VERSION 5.8 ;
BUSBITCHARS "[]" ;
DIVIDERCHAR "/" ;
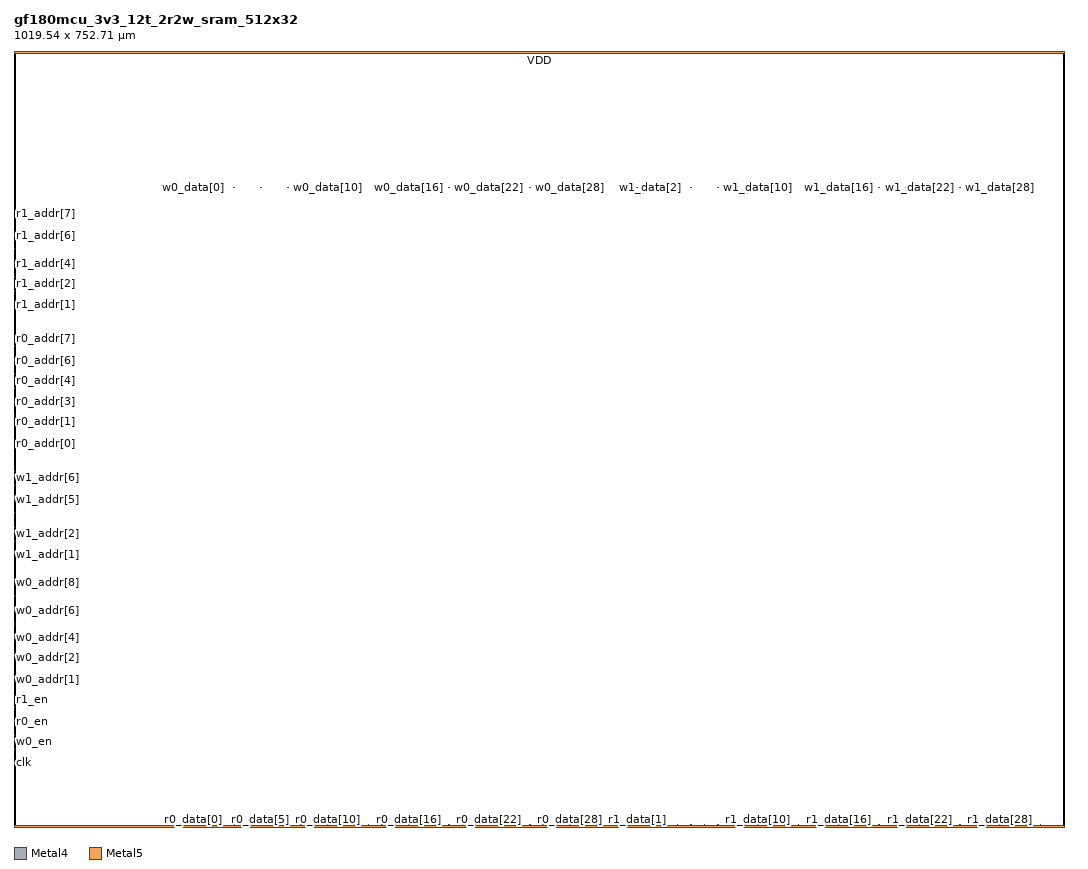
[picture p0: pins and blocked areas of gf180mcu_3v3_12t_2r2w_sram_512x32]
MACRO gf180mcu_3v3_12t_2r2w_sram_512x32
  CLASS BLOCK ;
  FOREIGN gf180mcu_3v3_12t_2r2w_sram_512x32 0.000 0.000 ;
  ORIGIN 0.000 0.000 ;
  SIZE 1019.545000 BY 752.710000 ;
  SYMMETRY X Y ;
  PIN clk
    DIRECTION INPUT ;
    USE SIGNAL ;
    PORT
      LAYER Metal4 ;
        RECT 0.320000 61.970000 0.960000 62.610000 ;
    END
  END clk
  PIN w0_en
    DIRECTION INPUT ;
    USE SIGNAL ;
    PORT
      LAYER Metal4 ;
        RECT 0.320000 75.455000 0.960000 76.095000 ;
    END
  END w0_en
  PIN w1_en
    DIRECTION INPUT ;
    USE SIGNAL ;
    PORT
      LAYER Metal4 ;
        RECT 0.320000 88.935000 0.960000 89.575000 ;
    END
  END w1_en
  PIN r0_en
    DIRECTION INPUT ;
    USE SIGNAL ;
    PORT
      LAYER Metal4 ;
        RECT 0.320000 102.415000 0.960000 103.055000 ;
    END
  END r0_en
  PIN r1_en
    DIRECTION INPUT ;
    USE SIGNAL ;
    PORT
      LAYER Metal4 ;
        RECT 0.320000 115.900000 0.960000 116.540000 ;
    END
  END r1_en
  PIN w0_addr[0]
    DIRECTION INPUT ;
    USE SIGNAL ;
    PORT
      LAYER Metal4 ;
        RECT 0.320000 129.380000 0.960000 130.020000 ;
    END
  END w0_addr[0]
  PIN w0_addr[1]
    DIRECTION INPUT ;
    USE SIGNAL ;
    PORT
      LAYER Metal4 ;
        RECT 0.320000 142.865000 0.960000 143.505000 ;
    END
  END w0_addr[1]
  PIN w0_addr[2]
    DIRECTION INPUT ;
    USE SIGNAL ;
    PORT
      LAYER Metal4 ;
        RECT 0.320000 156.345000 0.960000 156.985000 ;
    END
  END w0_addr[2]
  PIN w0_addr[3]
    DIRECTION INPUT ;
    USE SIGNAL ;
    PORT
      LAYER Metal4 ;
        RECT 0.320000 169.825000 0.960000 170.465000 ;
    END
  END w0_addr[3]
  PIN w0_addr[4]
    DIRECTION INPUT ;
    USE SIGNAL ;
    PORT
      LAYER Metal4 ;
        RECT 0.320000 183.310000 0.960000 183.950000 ;
    END
  END w0_addr[4]
  PIN w0_addr[5]
    DIRECTION INPUT ;
    USE SIGNAL ;
    PORT
      LAYER Metal4 ;
        RECT 0.320000 196.790000 0.960000 197.430000 ;
    END
  END w0_addr[5]
  PIN w0_addr[6]
    DIRECTION INPUT ;
    USE SIGNAL ;
    PORT
      LAYER Metal4 ;
        RECT 0.320000 210.270000 0.960000 210.910000 ;
    END
  END w0_addr[6]
  PIN w0_addr[7]
    DIRECTION INPUT ;
    USE SIGNAL ;
    PORT
      LAYER Metal4 ;
        RECT 0.320000 223.755000 0.960000 224.395000 ;
    END
  END w0_addr[7]
  PIN w0_addr[8]
    DIRECTION INPUT ;
    USE SIGNAL ;
    PORT
      LAYER Metal4 ;
        RECT 0.320000 237.235000 0.960000 237.875000 ;
    END
  END w0_addr[8]
  PIN w1_addr[0]
    DIRECTION INPUT ;
    USE SIGNAL ;
    PORT
      LAYER Metal4 ;
        RECT 0.320000 250.720000 0.960000 251.360000 ;
    END
  END w1_addr[0]
  PIN w1_addr[1]
    DIRECTION INPUT ;
    USE SIGNAL ;
    PORT
      LAYER Metal4 ;
        RECT 0.320000 264.200000 0.960000 264.840000 ;
    END
  END w1_addr[1]
  PIN w1_addr[2]
    DIRECTION INPUT ;
    USE SIGNAL ;
    PORT
      LAYER Metal4 ;
        RECT 0.320000 277.680000 0.960000 278.320000 ;
    END
  END w1_addr[2]
  PIN w1_addr[3]
    DIRECTION INPUT ;
    USE SIGNAL ;
    PORT
      LAYER Metal4 ;
        RECT 0.320000 291.165000 0.960000 291.805000 ;
    END
  END w1_addr[3]
  PIN w1_addr[4]
    DIRECTION INPUT ;
    USE SIGNAL ;
    PORT
      LAYER Metal4 ;
        RECT 0.320000 304.645000 0.960000 305.285000 ;
    END
  END w1_addr[4]
  PIN w1_addr[5]
    DIRECTION INPUT ;
    USE SIGNAL ;
    PORT
      LAYER Metal4 ;
        RECT 0.320000 318.130000 0.960000 318.770000 ;
    END
  END w1_addr[5]
  PIN w1_addr[6]
    DIRECTION INPUT ;
    USE SIGNAL ;
    PORT
      LAYER Metal4 ;
        RECT 0.320000 331.610000 0.960000 332.250000 ;
    END
  END w1_addr[6]
  PIN w1_addr[7]
    DIRECTION INPUT ;
    USE SIGNAL ;
    PORT
      LAYER Metal4 ;
        RECT 0.320000 345.090000 0.960000 345.730000 ;
    END
  END w1_addr[7]
  PIN w1_addr[8]
    DIRECTION INPUT ;
    USE SIGNAL ;
    PORT
      LAYER Metal4 ;
        RECT 0.320000 358.575000 0.960000 359.215000 ;
    END
  END w1_addr[8]
  PIN r0_addr[0]
    DIRECTION INPUT ;
    USE SIGNAL ;
    PORT
      LAYER Metal4 ;
        RECT 0.320000 372.055000 0.960000 372.695000 ;
    END
  END r0_addr[0]
  PIN r0_addr[1]
    DIRECTION INPUT ;
    USE SIGNAL ;
    PORT
      LAYER Metal4 ;
        RECT 0.320000 385.540000 0.960000 386.180000 ;
    END
  END r0_addr[1]
  PIN r0_addr[2]
    DIRECTION INPUT ;
    USE SIGNAL ;
    PORT
      LAYER Metal4 ;
        RECT 0.320000 399.020000 0.960000 399.660000 ;
    END
  END r0_addr[2]
  PIN r0_addr[3]
    DIRECTION INPUT ;
    USE SIGNAL ;
    PORT
      LAYER Metal4 ;
        RECT 0.320000 412.500000 0.960000 413.140000 ;
    END
  END r0_addr[3]
  PIN r0_addr[4]
    DIRECTION INPUT ;
    USE SIGNAL ;
    PORT
      LAYER Metal4 ;
        RECT 0.320000 425.985000 0.960000 426.625000 ;
    END
  END r0_addr[4]
  PIN r0_addr[5]
    DIRECTION INPUT ;
    USE SIGNAL ;
    PORT
      LAYER Metal4 ;
        RECT 0.320000 439.465000 0.960000 440.105000 ;
    END
  END r0_addr[5]
  PIN r0_addr[6]
    DIRECTION INPUT ;
    USE SIGNAL ;
    PORT
      LAYER Metal4 ;
        RECT 0.320000 452.950000 0.960000 453.590000 ;
    END
  END r0_addr[6]
  PIN r0_addr[7]
    DIRECTION INPUT ;
    USE SIGNAL ;
    PORT
      LAYER Metal4 ;
        RECT 0.320000 466.430000 0.960000 467.070000 ;
    END
  END r0_addr[7]
  PIN r0_addr[8]
    DIRECTION INPUT ;
    USE SIGNAL ;
    PORT
      LAYER Metal4 ;
        RECT 0.320000 479.910000 0.960000 480.550000 ;
    END
  END r0_addr[8]
  PIN r1_addr[0]
    DIRECTION INPUT ;
    USE SIGNAL ;
    PORT
      LAYER Metal4 ;
        RECT 0.320000 493.395000 0.960000 494.035000 ;
    END
  END r1_addr[0]
  PIN r1_addr[1]
    DIRECTION INPUT ;
    USE SIGNAL ;
    PORT
      LAYER Metal4 ;
        RECT 0.320000 506.875000 0.960000 507.515000 ;
    END
  END r1_addr[1]
  PIN r1_addr[2]
    DIRECTION INPUT ;
    USE SIGNAL ;
    PORT
      LAYER Metal4 ;
        RECT 0.320000 520.355000 0.960000 520.995000 ;
    END
  END r1_addr[2]
  PIN r1_addr[3]
    DIRECTION INPUT ;
    USE SIGNAL ;
    PORT
      LAYER Metal4 ;
        RECT 0.320000 533.840000 0.960000 534.480000 ;
    END
  END r1_addr[3]
  PIN r1_addr[4]
    DIRECTION INPUT ;
    USE SIGNAL ;
    PORT
      LAYER Metal4 ;
        RECT 0.320000 547.320000 0.960000 547.960000 ;
    END
  END r1_addr[4]
  PIN r1_addr[5]
    DIRECTION INPUT ;
    USE SIGNAL ;
    PORT
      LAYER Metal4 ;
        RECT 0.320000 560.805000 0.960000 561.445000 ;
    END
  END r1_addr[5]
  PIN r1_addr[6]
    DIRECTION INPUT ;
    USE SIGNAL ;
    PORT
      LAYER Metal4 ;
        RECT 0.320000 574.285000 0.960000 574.925000 ;
    END
  END r1_addr[6]
  PIN r1_addr[7]
    DIRECTION INPUT ;
    USE SIGNAL ;
    PORT
      LAYER Metal4 ;
        RECT 0.320000 587.765000 0.960000 588.405000 ;
    END
  END r1_addr[7]
  PIN r1_addr[8]
    DIRECTION INPUT ;
    USE SIGNAL ;
    PORT
      LAYER Metal4 ;
        RECT 0.320000 601.250000 0.960000 601.890000 ;
    END
  END r1_addr[8]
  PIN w0_data[0]
    DIRECTION INPUT ;
    USE SIGNAL ;
    PORT
      LAYER Metal5 ;
        RECT 174.205000 620.630000 174.845000 621.270000 ;
    END
  END w0_data[0]
  PIN w0_data[1]
    DIRECTION INPUT ;
    USE SIGNAL ;
    PORT
      LAYER Metal5 ;
        RECT 187.260000 620.630000 187.900000 621.270000 ;
    END
  END w0_data[1]
  PIN w0_data[2]
    DIRECTION INPUT ;
    USE SIGNAL ;
    PORT
      LAYER Metal5 ;
        RECT 200.310000 620.630000 200.950000 621.270000 ;
    END
  END w0_data[2]
  PIN w0_data[3]
    DIRECTION INPUT ;
    USE SIGNAL ;
    PORT
      LAYER Metal5 ;
        RECT 213.360000 620.630000 214.000000 621.270000 ;
    END
  END w0_data[3]
  PIN w0_data[4]
    DIRECTION INPUT ;
    USE SIGNAL ;
    PORT
      LAYER Metal5 ;
        RECT 226.415000 620.630000 227.055000 621.270000 ;
    END
  END w0_data[4]
  PIN w0_data[5]
    DIRECTION INPUT ;
    USE SIGNAL ;
    PORT
      LAYER Metal5 ;
        RECT 239.465000 620.630000 240.105000 621.270000 ;
    END
  END w0_data[5]
  PIN w0_data[6]
    DIRECTION INPUT ;
    USE SIGNAL ;
    PORT
      LAYER Metal5 ;
        RECT 252.515000 620.630000 253.155000 621.270000 ;
    END
  END w0_data[6]
  PIN w0_data[7]
    DIRECTION INPUT ;
    USE SIGNAL ;
    PORT
      LAYER Metal5 ;
        RECT 265.570000 620.630000 266.210000 621.270000 ;
    END
  END w0_data[7]
  PIN w0_data[8]
    DIRECTION INPUT ;
    USE SIGNAL ;
    PORT
      LAYER Metal5 ;
        RECT 278.620000 620.630000 279.260000 621.270000 ;
    END
  END w0_data[8]
  PIN w0_data[9]
    DIRECTION INPUT ;
    USE SIGNAL ;
    PORT
      LAYER Metal5 ;
        RECT 291.675000 620.630000 292.315000 621.270000 ;
    END
  END w0_data[9]
  PIN w0_data[10]
    DIRECTION INPUT ;
    USE SIGNAL ;
    PORT
      LAYER Metal5 ;
        RECT 304.725000 620.630000 305.365000 621.270000 ;
    END
  END w0_data[10]
  PIN w0_data[11]
    DIRECTION INPUT ;
    USE SIGNAL ;
    PORT
      LAYER Metal5 ;
        RECT 317.775000 620.630000 318.415000 621.270000 ;
    END
  END w0_data[11]
  PIN w0_data[12]
    DIRECTION INPUT ;
    USE SIGNAL ;
    PORT
      LAYER Metal5 ;
        RECT 330.830000 620.630000 331.470000 621.270000 ;
    END
  END w0_data[12]
  PIN w0_data[13]
    DIRECTION INPUT ;
    USE SIGNAL ;
    PORT
      LAYER Metal5 ;
        RECT 343.880000 620.630000 344.520000 621.270000 ;
    END
  END w0_data[13]
  PIN w0_data[14]
    DIRECTION INPUT ;
    USE SIGNAL ;
    PORT
      LAYER Metal5 ;
        RECT 356.930000 620.630000 357.570000 621.270000 ;
    END
  END w0_data[14]
  PIN w0_data[15]
    DIRECTION INPUT ;
    USE SIGNAL ;
    PORT
      LAYER Metal5 ;
        RECT 369.985000 620.630000 370.625000 621.270000 ;
    END
  END w0_data[15]
  PIN w0_data[16]
    DIRECTION INPUT ;
    USE SIGNAL ;
    PORT
      LAYER Metal5 ;
        RECT 383.035000 620.630000 383.675000 621.270000 ;
    END
  END w0_data[16]
  PIN w0_data[17]
    DIRECTION INPUT ;
    USE SIGNAL ;
    PORT
      LAYER Metal5 ;
        RECT 396.090000 620.630000 396.730000 621.270000 ;
    END
  END w0_data[17]
  PIN w0_data[18]
    DIRECTION INPUT ;
    USE SIGNAL ;
    PORT
      LAYER Metal5 ;
        RECT 409.140000 620.630000 409.780000 621.270000 ;
    END
  END w0_data[18]
  PIN w0_data[19]
    DIRECTION INPUT ;
    USE SIGNAL ;
    PORT
      LAYER Metal5 ;
        RECT 422.190000 620.630000 422.830000 621.270000 ;
    END
  END w0_data[19]
  PIN w0_data[20]
    DIRECTION INPUT ;
    USE SIGNAL ;
    PORT
      LAYER Metal5 ;
        RECT 435.245000 620.630000 435.885000 621.270000 ;
    END
  END w0_data[20]
  PIN w0_data[21]
    DIRECTION INPUT ;
    USE SIGNAL ;
    PORT
      LAYER Metal5 ;
        RECT 448.295000 620.630000 448.935000 621.270000 ;
    END
  END w0_data[21]
  PIN w0_data[22]
    DIRECTION INPUT ;
    USE SIGNAL ;
    PORT
      LAYER Metal5 ;
        RECT 461.345000 620.630000 461.985000 621.270000 ;
    END
  END w0_data[22]
  PIN w0_data[23]
    DIRECTION INPUT ;
    USE SIGNAL ;
    PORT
      LAYER Metal5 ;
        RECT 474.400000 620.630000 475.040000 621.270000 ;
    END
  END w0_data[23]
  PIN w0_data[24]
    DIRECTION INPUT ;
    USE SIGNAL ;
    PORT
      LAYER Metal5 ;
        RECT 487.450000 620.630000 488.090000 621.270000 ;
    END
  END w0_data[24]
  PIN w0_data[25]
    DIRECTION INPUT ;
    USE SIGNAL ;
    PORT
      LAYER Metal5 ;
        RECT 500.505000 620.630000 501.145000 621.270000 ;
    END
  END w0_data[25]
  PIN w0_data[26]
    DIRECTION INPUT ;
    USE SIGNAL ;
    PORT
      LAYER Metal5 ;
        RECT 513.555000 620.630000 514.195000 621.270000 ;
    END
  END w0_data[26]
  PIN w0_data[27]
    DIRECTION INPUT ;
    USE SIGNAL ;
    PORT
      LAYER Metal5 ;
        RECT 526.605000 620.630000 527.245000 621.270000 ;
    END
  END w0_data[27]
  PIN w0_data[28]
    DIRECTION INPUT ;
    USE SIGNAL ;
    PORT
      LAYER Metal5 ;
        RECT 539.660000 620.630000 540.300000 621.270000 ;
    END
  END w0_data[28]
  PIN w0_data[29]
    DIRECTION INPUT ;
    USE SIGNAL ;
    PORT
      LAYER Metal5 ;
        RECT 552.710000 620.630000 553.350000 621.270000 ;
    END
  END w0_data[29]
  PIN w0_data[30]
    DIRECTION INPUT ;
    USE SIGNAL ;
    PORT
      LAYER Metal5 ;
        RECT 565.760000 620.630000 566.400000 621.270000 ;
    END
  END w0_data[30]
  PIN w0_data[31]
    DIRECTION INPUT ;
    USE SIGNAL ;
    PORT
      LAYER Metal5 ;
        RECT 578.815000 620.630000 579.455000 621.270000 ;
    END
  END w0_data[31]
  PIN w1_data[0]
    DIRECTION INPUT ;
    USE SIGNAL ;
    PORT
      LAYER Metal5 ;
        RECT 591.865000 620.630000 592.505000 621.270000 ;
    END
  END w1_data[0]
  PIN w1_data[1]
    DIRECTION INPUT ;
    USE SIGNAL ;
    PORT
      LAYER Metal5 ;
        RECT 604.920000 620.630000 605.560000 621.270000 ;
    END
  END w1_data[1]
  PIN w1_data[2]
    DIRECTION INPUT ;
    USE SIGNAL ;
    PORT
      LAYER Metal5 ;
        RECT 617.970000 620.630000 618.610000 621.270000 ;
    END
  END w1_data[2]
  PIN w1_data[3]
    DIRECTION INPUT ;
    USE SIGNAL ;
    PORT
      LAYER Metal5 ;
        RECT 631.020000 620.630000 631.660000 621.270000 ;
    END
  END w1_data[3]
  PIN w1_data[4]
    DIRECTION INPUT ;
    USE SIGNAL ;
    PORT
      LAYER Metal5 ;
        RECT 644.075000 620.630000 644.715000 621.270000 ;
    END
  END w1_data[4]
  PIN w1_data[5]
    DIRECTION INPUT ;
    USE SIGNAL ;
    PORT
      LAYER Metal5 ;
        RECT 657.125000 620.630000 657.765000 621.270000 ;
    END
  END w1_data[5]
  PIN w1_data[6]
    DIRECTION INPUT ;
    USE SIGNAL ;
    PORT
      LAYER Metal5 ;
        RECT 670.175000 620.630000 670.815000 621.270000 ;
    END
  END w1_data[6]
  PIN w1_data[7]
    DIRECTION INPUT ;
    USE SIGNAL ;
    PORT
      LAYER Metal5 ;
        RECT 683.230000 620.630000 683.870000 621.270000 ;
    END
  END w1_data[7]
  PIN w1_data[8]
    DIRECTION INPUT ;
    USE SIGNAL ;
    PORT
      LAYER Metal5 ;
        RECT 696.280000 620.630000 696.920000 621.270000 ;
    END
  END w1_data[8]
  PIN w1_data[9]
    DIRECTION INPUT ;
    USE SIGNAL ;
    PORT
      LAYER Metal5 ;
        RECT 709.335000 620.630000 709.975000 621.270000 ;
    END
  END w1_data[9]
  PIN w1_data[10]
    DIRECTION INPUT ;
    USE SIGNAL ;
    PORT
      LAYER Metal5 ;
        RECT 722.385000 620.630000 723.025000 621.270000 ;
    END
  END w1_data[10]
  PIN w1_data[11]
    DIRECTION INPUT ;
    USE SIGNAL ;
    PORT
      LAYER Metal5 ;
        RECT 735.435000 620.630000 736.075000 621.270000 ;
    END
  END w1_data[11]
  PIN w1_data[12]
    DIRECTION INPUT ;
    USE SIGNAL ;
    PORT
      LAYER Metal5 ;
        RECT 748.490000 620.630000 749.130000 621.270000 ;
    END
  END w1_data[12]
  PIN w1_data[13]
    DIRECTION INPUT ;
    USE SIGNAL ;
    PORT
      LAYER Metal5 ;
        RECT 761.540000 620.630000 762.180000 621.270000 ;
    END
  END w1_data[13]
  PIN w1_data[14]
    DIRECTION INPUT ;
    USE SIGNAL ;
    PORT
      LAYER Metal5 ;
        RECT 774.590000 620.630000 775.230000 621.270000 ;
    END
  END w1_data[14]
  PIN w1_data[15]
    DIRECTION INPUT ;
    USE SIGNAL ;
    PORT
      LAYER Metal5 ;
        RECT 787.645000 620.630000 788.285000 621.270000 ;
    END
  END w1_data[15]
  PIN w1_data[16]
    DIRECTION INPUT ;
    USE SIGNAL ;
    PORT
      LAYER Metal5 ;
        RECT 800.695000 620.630000 801.335000 621.270000 ;
    END
  END w1_data[16]
  PIN w1_data[17]
    DIRECTION INPUT ;
    USE SIGNAL ;
    PORT
      LAYER Metal5 ;
        RECT 813.750000 620.630000 814.390000 621.270000 ;
    END
  END w1_data[17]
  PIN w1_data[18]
    DIRECTION INPUT ;
    USE SIGNAL ;
    PORT
      LAYER Metal5 ;
        RECT 826.800000 620.630000 827.440000 621.270000 ;
    END
  END w1_data[18]
  PIN w1_data[19]
    DIRECTION INPUT ;
    USE SIGNAL ;
    PORT
      LAYER Metal5 ;
        RECT 839.850000 620.630000 840.490000 621.270000 ;
    END
  END w1_data[19]
  PIN w1_data[20]
    DIRECTION INPUT ;
    USE SIGNAL ;
    PORT
      LAYER Metal5 ;
        RECT 852.905000 620.630000 853.545000 621.270000 ;
    END
  END w1_data[20]
  PIN w1_data[21]
    DIRECTION INPUT ;
    USE SIGNAL ;
    PORT
      LAYER Metal5 ;
        RECT 865.955000 620.630000 866.595000 621.270000 ;
    END
  END w1_data[21]
  PIN w1_data[22]
    DIRECTION INPUT ;
    USE SIGNAL ;
    PORT
      LAYER Metal5 ;
        RECT 879.005000 620.630000 879.645000 621.270000 ;
    END
  END w1_data[22]
  PIN w1_data[23]
    DIRECTION INPUT ;
    USE SIGNAL ;
    PORT
      LAYER Metal5 ;
        RECT 892.060000 620.630000 892.700000 621.270000 ;
    END
  END w1_data[23]
  PIN w1_data[24]
    DIRECTION INPUT ;
    USE SIGNAL ;
    PORT
      LAYER Metal5 ;
        RECT 905.110000 620.630000 905.750000 621.270000 ;
    END
  END w1_data[24]
  PIN w1_data[25]
    DIRECTION INPUT ;
    USE SIGNAL ;
    PORT
      LAYER Metal5 ;
        RECT 918.165000 620.630000 918.805000 621.270000 ;
    END
  END w1_data[25]
  PIN w1_data[26]
    DIRECTION INPUT ;
    USE SIGNAL ;
    PORT
      LAYER Metal5 ;
        RECT 931.215000 620.630000 931.855000 621.270000 ;
    END
  END w1_data[26]
  PIN w1_data[27]
    DIRECTION INPUT ;
    USE SIGNAL ;
    PORT
      LAYER Metal5 ;
        RECT 944.265000 620.630000 944.905000 621.270000 ;
    END
  END w1_data[27]
  PIN w1_data[28]
    DIRECTION INPUT ;
    USE SIGNAL ;
    PORT
      LAYER Metal5 ;
        RECT 957.320000 620.630000 957.960000 621.270000 ;
    END
  END w1_data[28]
  PIN w1_data[29]
    DIRECTION INPUT ;
    USE SIGNAL ;
    PORT
      LAYER Metal5 ;
        RECT 970.370000 620.630000 971.010000 621.270000 ;
    END
  END w1_data[29]
  PIN w1_data[30]
    DIRECTION INPUT ;
    USE SIGNAL ;
    PORT
      LAYER Metal5 ;
        RECT 983.420000 620.630000 984.060000 621.270000 ;
    END
  END w1_data[30]
  PIN w1_data[31]
    DIRECTION INPUT ;
    USE SIGNAL ;
    PORT
      LAYER Metal5 ;
        RECT 996.475000 620.630000 997.115000 621.270000 ;
    END
  END w1_data[31]
  PIN r0_data[0]
    DIRECTION OUTPUT ;
    USE SIGNAL ;
    PORT
      LAYER Metal5 ;
        RECT 174.205000 1.680000 174.845000 2.320000 ;
    END
  END r0_data[0]
  PIN r0_data[1]
    DIRECTION OUTPUT ;
    USE SIGNAL ;
    PORT
      LAYER Metal5 ;
        RECT 187.260000 1.680000 187.900000 2.320000 ;
    END
  END r0_data[1]
  PIN r0_data[2]
    DIRECTION OUTPUT ;
    USE SIGNAL ;
    PORT
      LAYER Metal5 ;
        RECT 200.310000 1.680000 200.950000 2.320000 ;
    END
  END r0_data[2]
  PIN r0_data[3]
    DIRECTION OUTPUT ;
    USE SIGNAL ;
    PORT
      LAYER Metal5 ;
        RECT 213.360000 1.680000 214.000000 2.320000 ;
    END
  END r0_data[3]
  PIN r0_data[4]
    DIRECTION OUTPUT ;
    USE SIGNAL ;
    PORT
      LAYER Metal5 ;
        RECT 226.415000 1.680000 227.055000 2.320000 ;
    END
  END r0_data[4]
  PIN r0_data[5]
    DIRECTION OUTPUT ;
    USE SIGNAL ;
    PORT
      LAYER Metal5 ;
        RECT 239.465000 1.680000 240.105000 2.320000 ;
    END
  END r0_data[5]
  PIN r0_data[6]
    DIRECTION OUTPUT ;
    USE SIGNAL ;
    PORT
      LAYER Metal5 ;
        RECT 252.515000 1.680000 253.155000 2.320000 ;
    END
  END r0_data[6]
  PIN r0_data[7]
    DIRECTION OUTPUT ;
    USE SIGNAL ;
    PORT
      LAYER Metal5 ;
        RECT 265.570000 1.680000 266.210000 2.320000 ;
    END
  END r0_data[7]
  PIN r0_data[8]
    DIRECTION OUTPUT ;
    USE SIGNAL ;
    PORT
      LAYER Metal5 ;
        RECT 278.620000 1.680000 279.260000 2.320000 ;
    END
  END r0_data[8]
  PIN r0_data[9]
    DIRECTION OUTPUT ;
    USE SIGNAL ;
    PORT
      LAYER Metal5 ;
        RECT 291.675000 1.680000 292.315000 2.320000 ;
    END
  END r0_data[9]
  PIN r0_data[10]
    DIRECTION OUTPUT ;
    USE SIGNAL ;
    PORT
      LAYER Metal5 ;
        RECT 304.725000 1.680000 305.365000 2.320000 ;
    END
  END r0_data[10]
  PIN r0_data[11]
    DIRECTION OUTPUT ;
    USE SIGNAL ;
    PORT
      LAYER Metal5 ;
        RECT 317.775000 1.680000 318.415000 2.320000 ;
    END
  END r0_data[11]
  PIN r0_data[12]
    DIRECTION OUTPUT ;
    USE SIGNAL ;
    PORT
      LAYER Metal5 ;
        RECT 330.830000 1.680000 331.470000 2.320000 ;
    END
  END r0_data[12]
  PIN r0_data[13]
    DIRECTION OUTPUT ;
    USE SIGNAL ;
    PORT
      LAYER Metal5 ;
        RECT 343.880000 1.680000 344.520000 2.320000 ;
    END
  END r0_data[13]
  PIN r0_data[14]
    DIRECTION OUTPUT ;
    USE SIGNAL ;
    PORT
      LAYER Metal5 ;
        RECT 356.930000 1.680000 357.570000 2.320000 ;
    END
  END r0_data[14]
  PIN r0_data[15]
    DIRECTION OUTPUT ;
    USE SIGNAL ;
    PORT
      LAYER Metal5 ;
        RECT 369.985000 1.680000 370.625000 2.320000 ;
    END
  END r0_data[15]
  PIN r0_data[16]
    DIRECTION OUTPUT ;
    USE SIGNAL ;
    PORT
      LAYER Metal5 ;
        RECT 383.035000 1.680000 383.675000 2.320000 ;
    END
  END r0_data[16]
  PIN r0_data[17]
    DIRECTION OUTPUT ;
    USE SIGNAL ;
    PORT
      LAYER Metal5 ;
        RECT 396.090000 1.680000 396.730000 2.320000 ;
    END
  END r0_data[17]
  PIN r0_data[18]
    DIRECTION OUTPUT ;
    USE SIGNAL ;
    PORT
      LAYER Metal5 ;
        RECT 409.140000 1.680000 409.780000 2.320000 ;
    END
  END r0_data[18]
  PIN r0_data[19]
    DIRECTION OUTPUT ;
    USE SIGNAL ;
    PORT
      LAYER Metal5 ;
        RECT 422.190000 1.680000 422.830000 2.320000 ;
    END
  END r0_data[19]
  PIN r0_data[20]
    DIRECTION OUTPUT ;
    USE SIGNAL ;
    PORT
      LAYER Metal5 ;
        RECT 435.245000 1.680000 435.885000 2.320000 ;
    END
  END r0_data[20]
  PIN r0_data[21]
    DIRECTION OUTPUT ;
    USE SIGNAL ;
    PORT
      LAYER Metal5 ;
        RECT 448.295000 1.680000 448.935000 2.320000 ;
    END
  END r0_data[21]
  PIN r0_data[22]
    DIRECTION OUTPUT ;
    USE SIGNAL ;
    PORT
      LAYER Metal5 ;
        RECT 461.345000 1.680000 461.985000 2.320000 ;
    END
  END r0_data[22]
  PIN r0_data[23]
    DIRECTION OUTPUT ;
    USE SIGNAL ;
    PORT
      LAYER Metal5 ;
        RECT 474.400000 1.680000 475.040000 2.320000 ;
    END
  END r0_data[23]
  PIN r0_data[24]
    DIRECTION OUTPUT ;
    USE SIGNAL ;
    PORT
      LAYER Metal5 ;
        RECT 487.450000 1.680000 488.090000 2.320000 ;
    END
  END r0_data[24]
  PIN r0_data[25]
    DIRECTION OUTPUT ;
    USE SIGNAL ;
    PORT
      LAYER Metal5 ;
        RECT 500.505000 1.680000 501.145000 2.320000 ;
    END
  END r0_data[25]
  PIN r0_data[26]
    DIRECTION OUTPUT ;
    USE SIGNAL ;
    PORT
      LAYER Metal5 ;
        RECT 513.555000 1.680000 514.195000 2.320000 ;
    END
  END r0_data[26]
  PIN r0_data[27]
    DIRECTION OUTPUT ;
    USE SIGNAL ;
    PORT
      LAYER Metal5 ;
        RECT 526.605000 1.680000 527.245000 2.320000 ;
    END
  END r0_data[27]
  PIN r0_data[28]
    DIRECTION OUTPUT ;
    USE SIGNAL ;
    PORT
      LAYER Metal5 ;
        RECT 539.660000 1.680000 540.300000 2.320000 ;
    END
  END r0_data[28]
  PIN r0_data[29]
    DIRECTION OUTPUT ;
    USE SIGNAL ;
    PORT
      LAYER Metal5 ;
        RECT 552.710000 1.680000 553.350000 2.320000 ;
    END
  END r0_data[29]
  PIN r0_data[30]
    DIRECTION OUTPUT ;
    USE SIGNAL ;
    PORT
      LAYER Metal5 ;
        RECT 565.760000 1.680000 566.400000 2.320000 ;
    END
  END r0_data[30]
  PIN r0_data[31]
    DIRECTION OUTPUT ;
    USE SIGNAL ;
    PORT
      LAYER Metal5 ;
        RECT 578.815000 1.680000 579.455000 2.320000 ;
    END
  END r0_data[31]
  PIN r1_data[0]
    DIRECTION OUTPUT ;
    USE SIGNAL ;
    PORT
      LAYER Metal5 ;
        RECT 591.865000 1.680000 592.505000 2.320000 ;
    END
  END r1_data[0]
  PIN r1_data[1]
    DIRECTION OUTPUT ;
    USE SIGNAL ;
    PORT
      LAYER Metal5 ;
        RECT 604.920000 1.680000 605.560000 2.320000 ;
    END
  END r1_data[1]
  PIN r1_data[2]
    DIRECTION OUTPUT ;
    USE SIGNAL ;
    PORT
      LAYER Metal5 ;
        RECT 617.970000 1.680000 618.610000 2.320000 ;
    END
  END r1_data[2]
  PIN r1_data[3]
    DIRECTION OUTPUT ;
    USE SIGNAL ;
    PORT
      LAYER Metal5 ;
        RECT 631.020000 1.680000 631.660000 2.320000 ;
    END
  END r1_data[3]
  PIN r1_data[4]
    DIRECTION OUTPUT ;
    USE SIGNAL ;
    PORT
      LAYER Metal5 ;
        RECT 644.075000 1.680000 644.715000 2.320000 ;
    END
  END r1_data[4]
  PIN r1_data[5]
    DIRECTION OUTPUT ;
    USE SIGNAL ;
    PORT
      LAYER Metal5 ;
        RECT 657.125000 1.680000 657.765000 2.320000 ;
    END
  END r1_data[5]
  PIN r1_data[6]
    DIRECTION OUTPUT ;
    USE SIGNAL ;
    PORT
      LAYER Metal5 ;
        RECT 670.175000 1.680000 670.815000 2.320000 ;
    END
  END r1_data[6]
  PIN r1_data[7]
    DIRECTION OUTPUT ;
    USE SIGNAL ;
    PORT
      LAYER Metal5 ;
        RECT 683.230000 1.680000 683.870000 2.320000 ;
    END
  END r1_data[7]
  PIN r1_data[8]
    DIRECTION OUTPUT ;
    USE SIGNAL ;
    PORT
      LAYER Metal5 ;
        RECT 696.280000 1.680000 696.920000 2.320000 ;
    END
  END r1_data[8]
  PIN r1_data[9]
    DIRECTION OUTPUT ;
    USE SIGNAL ;
    PORT
      LAYER Metal5 ;
        RECT 709.335000 1.680000 709.975000 2.320000 ;
    END
  END r1_data[9]
  PIN r1_data[10]
    DIRECTION OUTPUT ;
    USE SIGNAL ;
    PORT
      LAYER Metal5 ;
        RECT 722.385000 1.680000 723.025000 2.320000 ;
    END
  END r1_data[10]
  PIN r1_data[11]
    DIRECTION OUTPUT ;
    USE SIGNAL ;
    PORT
      LAYER Metal5 ;
        RECT 735.435000 1.680000 736.075000 2.320000 ;
    END
  END r1_data[11]
  PIN r1_data[12]
    DIRECTION OUTPUT ;
    USE SIGNAL ;
    PORT
      LAYER Metal5 ;
        RECT 748.490000 1.680000 749.130000 2.320000 ;
    END
  END r1_data[12]
  PIN r1_data[13]
    DIRECTION OUTPUT ;
    USE SIGNAL ;
    PORT
      LAYER Metal5 ;
        RECT 761.540000 1.680000 762.180000 2.320000 ;
    END
  END r1_data[13]
  PIN r1_data[14]
    DIRECTION OUTPUT ;
    USE SIGNAL ;
    PORT
      LAYER Metal5 ;
        RECT 774.590000 1.680000 775.230000 2.320000 ;
    END
  END r1_data[14]
  PIN r1_data[15]
    DIRECTION OUTPUT ;
    USE SIGNAL ;
    PORT
      LAYER Metal5 ;
        RECT 787.645000 1.680000 788.285000 2.320000 ;
    END
  END r1_data[15]
  PIN r1_data[16]
    DIRECTION OUTPUT ;
    USE SIGNAL ;
    PORT
      LAYER Metal5 ;
        RECT 800.695000 1.680000 801.335000 2.320000 ;
    END
  END r1_data[16]
  PIN r1_data[17]
    DIRECTION OUTPUT ;
    USE SIGNAL ;
    PORT
      LAYER Metal5 ;
        RECT 813.750000 1.680000 814.390000 2.320000 ;
    END
  END r1_data[17]
  PIN r1_data[18]
    DIRECTION OUTPUT ;
    USE SIGNAL ;
    PORT
      LAYER Metal5 ;
        RECT 826.800000 1.680000 827.440000 2.320000 ;
    END
  END r1_data[18]
  PIN r1_data[19]
    DIRECTION OUTPUT ;
    USE SIGNAL ;
    PORT
      LAYER Metal5 ;
        RECT 839.850000 1.680000 840.490000 2.320000 ;
    END
  END r1_data[19]
  PIN r1_data[20]
    DIRECTION OUTPUT ;
    USE SIGNAL ;
    PORT
      LAYER Metal5 ;
        RECT 852.905000 1.680000 853.545000 2.320000 ;
    END
  END r1_data[20]
  PIN r1_data[21]
    DIRECTION OUTPUT ;
    USE SIGNAL ;
    PORT
      LAYER Metal5 ;
        RECT 865.955000 1.680000 866.595000 2.320000 ;
    END
  END r1_data[21]
  PIN r1_data[22]
    DIRECTION OUTPUT ;
    USE SIGNAL ;
    PORT
      LAYER Metal5 ;
        RECT 879.005000 1.680000 879.645000 2.320000 ;
    END
  END r1_data[22]
  PIN r1_data[23]
    DIRECTION OUTPUT ;
    USE SIGNAL ;
    PORT
      LAYER Metal5 ;
        RECT 892.060000 1.680000 892.700000 2.320000 ;
    END
  END r1_data[23]
  PIN r1_data[24]
    DIRECTION OUTPUT ;
    USE SIGNAL ;
    PORT
      LAYER Metal5 ;
        RECT 905.110000 1.680000 905.750000 2.320000 ;
    END
  END r1_data[24]
  PIN r1_data[25]
    DIRECTION OUTPUT ;
    USE SIGNAL ;
    PORT
      LAYER Metal5 ;
        RECT 918.165000 1.680000 918.805000 2.320000 ;
    END
  END r1_data[25]
  PIN r1_data[26]
    DIRECTION OUTPUT ;
    USE SIGNAL ;
    PORT
      LAYER Metal5 ;
        RECT 931.215000 1.680000 931.855000 2.320000 ;
    END
  END r1_data[26]
  PIN r1_data[27]
    DIRECTION OUTPUT ;
    USE SIGNAL ;
    PORT
      LAYER Metal5 ;
        RECT 944.265000 1.680000 944.905000 2.320000 ;
    END
  END r1_data[27]
  PIN r1_data[28]
    DIRECTION OUTPUT ;
    USE SIGNAL ;
    PORT
      LAYER Metal5 ;
        RECT 957.320000 1.680000 957.960000 2.320000 ;
    END
  END r1_data[28]
  PIN r1_data[29]
    DIRECTION OUTPUT ;
    USE SIGNAL ;
    PORT
      LAYER Metal5 ;
        RECT 970.370000 1.680000 971.010000 2.320000 ;
    END
  END r1_data[29]
  PIN r1_data[30]
    DIRECTION OUTPUT ;
    USE SIGNAL ;
    PORT
      LAYER Metal5 ;
        RECT 983.420000 1.680000 984.060000 2.320000 ;
    END
  END r1_data[30]
  PIN r1_data[31]
    DIRECTION OUTPUT ;
    USE SIGNAL ;
    PORT
      LAYER Metal5 ;
        RECT 996.475000 1.680000 997.115000 2.320000 ;
    END
  END r1_data[31]
  PIN VDD
    DIRECTION INOUT ;
    USE POWER ;
    PORT
      LAYER Metal5 ;
        RECT 0.000000 751.510000 1019.545000 752.710000 ;
    END
  END VDD
  PIN VSS
    DIRECTION INOUT ;
    USE GROUND ;
    PORT
      LAYER Metal5 ;
        RECT 0.000000 0.000000 1019.545000 1.200000 ;
    END
  END VSS
END gf180mcu_3v3_12t_2r2w_sram_512x32
END LIBRARY
